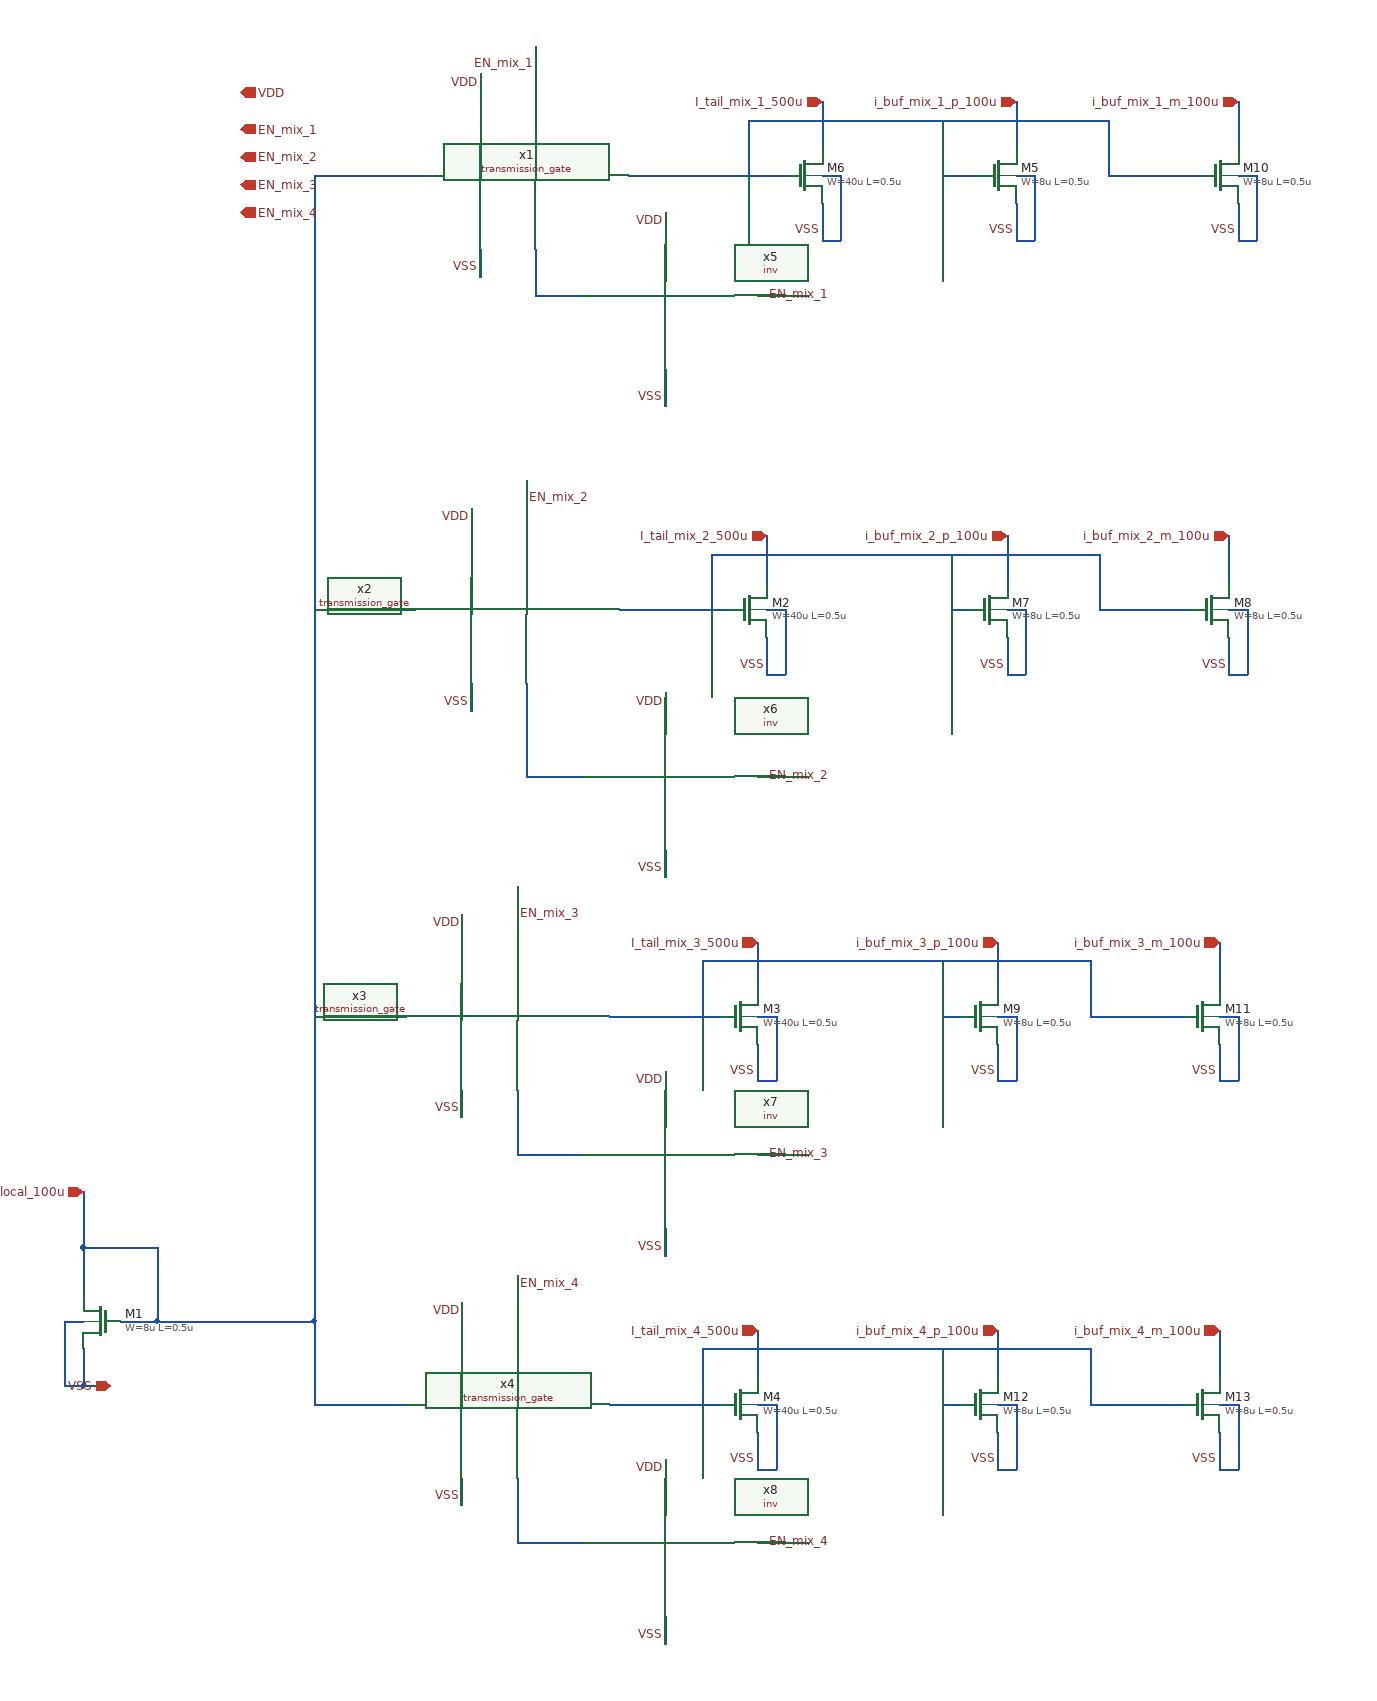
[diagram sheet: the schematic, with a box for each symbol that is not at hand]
v {xschem version=3.4.8RC file_version=1.3}
G {}
K {}
V {}
S {}
F {}
E {}
P 4 1 400 -950 {}
N 360 -770 360 -730 {lab=VSS}
N 360 -880 360 -830 {lab=I_local_100u}
N 360 -910 360 -880 {lab=I_local_100u}
N 360 -880 440 -880 {lab=I_local_100u}
N 440 -880 440 -800 {lab=I_local_100u}
N 400 -800 440 -800 {lab=I_local_100u}
N 340 -800 360 -800 {lab=VSS}
N 340 -800 340 -750 {lab=VSS}
N 340 -750 340 -730 {lab=VSS}
N 340 -730 360 -730 {lab=VSS}
N 440 -800 510 -800 {lab=I_local_100u}
N 360 -940 360 -910 {lab=I_local_100u}
N 1160 -2010 1160 -1970 {lab=VSS}
N 1160 -2120 1160 -2070 {lab=I_tail_mix_1_500u}
N 1160 -2040 1180 -2040 {lab=VSS}
N 1180 -2040 1180 -1970 {lab=VSS}
N 950 -2040 1060 -2040 {lab=#net1}
N 790 -2150 790 -2120 {lab=VDD}
N 610 -1910 610 -1630 {lab=I_local_100u}
N 610 -2040 730 -2040 {lab=I_local_100u}
N 610 -820 610 -800 {lab=I_local_100u}
N 610 -1630 610 -1390 {lab=I_local_100u}
N 790 -1960 790 -1930 {lab=VSS}
N 850 -2180 850 -2120 {lab=EN_mix_1}
N 850 -1960 850 -1920 {lab=#net2}
N 360 -730 390 -730 {lab=VSS}
N 1160 -1970 1180 -1970 {lab=VSS}
N 510 -800 610 -800 {lab=I_local_100u}
N 1100 -1540 1100 -1500 {lab=VSS}
N 1100 -1650 1100 -1600 {lab=I_tail_mix_2_500u}
N 1100 -1570 1120 -1570 {lab=VSS}
N 1120 -1570 1120 -1500 {lab=VSS}
N 1100 -1500 1120 -1500 {lab=VSS}
N 1000 -1570 1060 -1570 {lab=#net3}
N 1090 -1100 1090 -1060 {lab=VSS}
N 1090 -1210 1090 -1160 {lab=I_tail_mix_3_500u}
N 1090 -1130 1110 -1130 {lab=VSS}
N 1110 -1130 1110 -1060 {lab=VSS}
N 1090 -1060 1110 -1060 {lab=VSS}
N 990 -1130 1050 -1130 {lab=#net4}
N 1090 -680 1090 -640 {lab=VSS}
N 1090 -790 1090 -740 {lab=I_tail_mix_4_500u}
N 1090 -710 1110 -710 {lab=VSS}
N 1110 -710 1110 -640 {lab=VSS}
N 1090 -640 1110 -640 {lab=VSS}
N 990 -710 1050 -710 {lab=#net5}
N 780 -1680 780 -1650 {lab=VDD}
N 780 -1490 780 -1460 {lab=VSS}
N 840 -1710 840 -1650 {lab=EN_mix_2}
N 840 -1490 840 -1450 {lab=#net6}
N 770 -1240 770 -1210 {lab=VDD}
N 770 -1050 770 -1020 {lab=VSS}
N 830 -1270 830 -1210 {lab=EN_mix_3}
N 830 -1050 830 -1010 {lab=#net7}
N 770 -820 770 -790 {lab=VDD}
N 770 -630 770 -600 {lab=VSS}
N 830 -850 830 -790 {lab=EN_mix_4}
N 830 -630 830 -590 {lab=#net8}
N 930 -710 990 -710 {lab=#net5}
N 620 -710 710 -710 {lab=I_local_100u}
N 610 -1130 710 -1130 {lab=I_local_100u}
N 610 -710 620 -710 {lab=I_local_100u}
N 610 -1570 720 -1570 {lab=I_local_100u}
N 610 -2040 610 -1910 {lab=I_local_100u}
N 850 -1910 900 -1910 {lab=#net2}
N 850 -1920 850 -1910 {lab=#net2}
N 1090 -1910 1120 -1910 {lab=EN_mix_1}
N 1060 -2040 1120 -2040 {lab=#net1}
N 990 -2000 990 -1980 {lab=VDD}
N 990 -1830 990 -1790 {lab=VSS}
N 610 -1390 610 -830 {lab=I_local_100u}
N 610 -830 610 -820 {lab=I_local_100u}
N 940 -1570 1000 -1570 {lab=#net3}
N 840 -1390 900 -1390 {lab=#net6}
N 840 -1450 840 -1390 {lab=#net6}
N 990 -1310 990 -1280 {lab=VSS}
N 990 -1480 990 -1460 {lab=VDD}
N 1090 -1390 1120 -1390 {lab=EN_mix_2}
N 930 -1130 990 -1130 {lab=#net4}
N 840 -980 900 -980 {lab=#net7}
N 990 -900 990 -870 {lab=VSS}
N 990 -1070 990 -1050 {lab=VDD}
N 1090 -980 1120 -980 {lab=EN_mix_3}
N 830 -980 840 -980 {lab=#net7}
N 830 -1010 830 -980 {lab=#net7}
N 610 -800 610 -710 {lab=I_local_100u}
N 840 -560 900 -560 {lab=#net8}
N 990 -480 990 -450 {lab=VSS}
N 990 -650 990 -630 {lab=VDD}
N 1090 -560 1120 -560 {lab=EN_mix_4}
N 830 -560 840 -560 {lab=#net8}
N 830 -590 830 -560 {lab=#net8}
N 1370 -2010 1370 -1970 {lab=VSS}
N 1370 -2120 1370 -2070 {lab=i_buf_mix_1_p_100u}
N 1370 -2040 1390 -2040 {lab=VSS}
N 1390 -2040 1390 -1970 {lab=VSS}
N 1370 -1970 1390 -1970 {lab=VSS}
N 1610 -2010 1610 -1970 {lab=VSS}
N 1610 -2120 1610 -2070 {lab=i_buf_mix_1_m_100u}
N 1610 -2040 1630 -2040 {lab=VSS}
N 1630 -2040 1630 -1970 {lab=VSS}
N 1610 -1970 1630 -1970 {lab=VSS}
N 1470 -2100 1470 -2040 {lab=#net1}
N 1470 -2040 1480 -2040 {lab=#net1}
N 1480 -2040 1570 -2040 {lab=#net1}
N 1360 -1540 1360 -1500 {lab=VSS}
N 1360 -1650 1360 -1600 {lab=i_buf_mix_2_p_100u}
N 1360 -1570 1380 -1570 {lab=VSS}
N 1380 -1570 1380 -1500 {lab=VSS}
N 1360 -1500 1380 -1500 {lab=VSS}
N 1600 -1540 1600 -1500 {lab=VSS}
N 1600 -1650 1600 -1600 {lab=i_buf_mix_2_m_100u}
N 1600 -1570 1620 -1570 {lab=VSS}
N 1620 -1570 1620 -1500 {lab=VSS}
N 1600 -1500 1620 -1500 {lab=VSS}
N 1460 -1630 1460 -1570 {lab=#net3}
N 1460 -1570 1470 -1570 {lab=#net3}
N 1470 -1570 1560 -1570 {lab=#net3}
N 1350 -1100 1350 -1060 {lab=VSS}
N 1350 -1210 1350 -1160 {lab=i_buf_mix_3_p_100u}
N 1350 -1130 1370 -1130 {lab=VSS}
N 1370 -1130 1370 -1060 {lab=VSS}
N 1350 -1060 1370 -1060 {lab=VSS}
N 1590 -1100 1590 -1060 {lab=VSS}
N 1590 -1210 1590 -1160 {lab=i_buf_mix_3_m_100u}
N 1590 -1130 1610 -1130 {lab=VSS}
N 1610 -1130 1610 -1060 {lab=VSS}
N 1590 -1060 1610 -1060 {lab=VSS}
N 1450 -1190 1450 -1130 {lab=#net4}
N 1450 -1130 1460 -1130 {lab=#net4}
N 1460 -1130 1550 -1130 {lab=#net4}
N 1350 -680 1350 -640 {lab=VSS}
N 1350 -790 1350 -740 {lab=i_buf_mix_4_p_100u}
N 1350 -710 1370 -710 {lab=VSS}
N 1370 -710 1370 -640 {lab=VSS}
N 1350 -640 1370 -640 {lab=VSS}
N 1590 -680 1590 -640 {lab=VSS}
N 1590 -790 1590 -740 {lab=i_buf_mix_4_m_100u}
N 1590 -710 1610 -710 {lab=VSS}
N 1610 -710 1610 -640 {lab=VSS}
N 1590 -640 1610 -640 {lab=VSS}
N 1450 -770 1450 -710 {lab=#net5}
N 1450 -710 1460 -710 {lab=#net5}
N 1460 -710 1550 -710 {lab=#net5}
N 1080 -2100 1080 -2040 {lab=#net1}
N 1080 -2100 1470 -2100 {lab=#net1}
N 1290 -2040 1330 -2040 {lab=#net1}
N 1040 -1630 1460 -1630 {lab=#net3}
N 1040 -1630 1040 -1570 {lab=#net3}
N 1300 -1570 1320 -1570 {lab=#net3}
N 1300 -1630 1300 -1570 {lab=#net3}
N 1030 -1190 1450 -1190 {lab=#net4}
N 1030 -1190 1030 -1130 {lab=#net4}
N 1290 -1130 1310 -1130 {lab=#net4}
N 1290 -1190 1290 -1130 {lab=#net4}
N 1030 -770 1450 -770 {lab=#net5}
N 1030 -770 1030 -710 {lab=#net5}
N 1290 -710 1310 -710 {lab=#net5}
N 1290 -770 1290 -710 {lab=#net5}
N 1290 -2100 1290 -2040 {lab=#net1}
C {symbols/nfet_03v3.sym} 380 -800 0 1 {name=M1
L=0.5u
W=8u
nf=2
m=1
ad="'int((nf+1)/2) * W/nf * 0.18u'"
pd="'2*int((nf+1)/2) * (W/nf + 0.18u)'"
as="'int((nf+2)/2) * W/nf * 0.18u'"
ps="'2*int((nf+2)/2) * (W/nf + 0.18u)'"
nrd="'0.18u / W'" nrs="'0.18u / W'"
sa=0 sb=0 sd=0
model=nfet_03v3
spiceprefix=X
}
C {iopin.sym} 360 -940 0 0 {name=p5 lab=I_local_100u}
C {title.sym} 190 -60 0 0 {name=l1 author="Stefan Schippers"}
C {symbols/nfet_03v3.sym} 1140 -2040 0 0 {name=M6
L=0.5u
W=40u
nf=10
m=1
ad="'int((nf+1)/2) * W/nf * 0.18u'"
pd="'2*int((nf+1)/2) * (W/nf + 0.18u)'"
as="'int((nf+2)/2) * W/nf * 0.18u'"
ps="'2*int((nf+2)/2) * (W/nf + 0.18u)'"
nrd="'0.18u / W'" nrs="'0.18u / W'"
sa=0 sb=0 sd=0
model=nfet_03v3
spiceprefix=X
}
C {iopin.sym} 1160 -2120 0 0 {name=p12 lab=I_tail_mix_1_500u}
C {iopin.sym} 530 -2130 0 1 {name=p13 lab=VDD}
C {iopin.sym} 390 -730 0 0 {name=p2 lab=VSS}
C {lab_wire.sym} 790 -1940 0 0 {name=p14 sig_type=std_logic lab=VSS}
C {lab_wire.sym} 1160 -1980 0 0 {name=p15 sig_type=std_logic lab=VSS}
C {iopin.sym} 530 -2090 0 1 {name=p16 lab=EN_mix_1}
C {designs/digital/schematic/transmission_gate.sym} 850 -2040 0 0 {name=x1}
C {symbols/nfet_03v3.sym} 1080 -1570 0 0 {name=M2
L=0.5u
W=40u
nf=10
m=1
ad="'int((nf+1)/2) * W/nf * 0.18u'"
pd="'2*int((nf+1)/2) * (W/nf + 0.18u)'"
as="'int((nf+2)/2) * W/nf * 0.18u'"
ps="'2*int((nf+2)/2) * (W/nf + 0.18u)'"
nrd="'0.18u / W'" nrs="'0.18u / W'"
sa=0 sb=0 sd=0
model=nfet_03v3
spiceprefix=X
}
C {iopin.sym} 1100 -1650 0 0 {name=p1 lab=I_tail_mix_2_500u}
C {lab_wire.sym} 1100 -1510 0 0 {name=p3 sig_type=std_logic lab=VSS}
C {symbols/nfet_03v3.sym} 1070 -1130 0 0 {name=M3
L=0.5u
W=40u
nf=10
m=1
ad="'int((nf+1)/2) * W/nf * 0.18u'"
pd="'2*int((nf+1)/2) * (W/nf + 0.18u)'"
as="'int((nf+2)/2) * W/nf * 0.18u'"
ps="'2*int((nf+2)/2) * (W/nf + 0.18u)'"
nrd="'0.18u / W'" nrs="'0.18u / W'"
sa=0 sb=0 sd=0
model=nfet_03v3
spiceprefix=X
}
C {iopin.sym} 1090 -1210 0 0 {name=p4 lab=I_tail_mix_3_500u}
C {lab_wire.sym} 1090 -1070 0 0 {name=p6 sig_type=std_logic lab=VSS}
C {symbols/nfet_03v3.sym} 1070 -710 0 0 {name=M4
L=0.5u
W=40u
nf=10
m=1
ad="'int((nf+1)/2) * W/nf * 0.18u'"
pd="'2*int((nf+1)/2) * (W/nf + 0.18u)'"
as="'int((nf+2)/2) * W/nf * 0.18u'"
ps="'2*int((nf+2)/2) * (W/nf + 0.18u)'"
nrd="'0.18u / W'" nrs="'0.18u / W'"
sa=0 sb=0 sd=0
model=nfet_03v3
spiceprefix=X
}
C {iopin.sym} 1090 -790 0 0 {name=p7 lab=I_tail_mix_4_500u}
C {lab_wire.sym} 1090 -650 0 0 {name=p8 sig_type=std_logic lab=VSS}
C {lab_wire.sym} 780 -1470 0 0 {name=p10 sig_type=std_logic lab=VSS}
C {designs/digital/schematic/transmission_gate.sym} 840 -1570 0 0 {name=x2}
C {lab_wire.sym} 770 -1030 0 0 {name=p20 sig_type=std_logic lab=VSS}
C {designs/digital/schematic/transmission_gate.sym} 830 -1130 0 0 {name=x3}
C {lab_wire.sym} 770 -610 0 0 {name=p24 sig_type=std_logic lab=VSS}
C {designs/digital/schematic/transmission_gate.sym} 830 -710 0 0 {name=x4}
C {digital/schematic/inv.sym} 990 -1920 0 1 {name=x5}
C {lab_wire.sym} 990 -1800 0 0 {name=p17 sig_type=std_logic lab=VSS}
C {iopin.sym} 530 -2060 0 1 {name=p9 lab=EN_mix_2}
C {iopin.sym} 530 -2030 0 1 {name=p11 lab=EN_mix_3}
C {iopin.sym} 530 -2000 0 1 {name=p18 lab=EN_mix_4}
C {lab_wire.sym} 790 -2140 0 0 {name=p19 sig_type=std_logic lab=VDD}
C {lab_wire.sym} 780 -1670 0 0 {name=p21 sig_type=std_logic lab=VDD}
C {lab_wire.sym} 770 -1230 0 0 {name=p22 sig_type=std_logic lab=VDD}
C {lab_wire.sym} 770 -810 0 0 {name=p23 sig_type=std_logic lab=VDD}
C {lab_wire.sym} 850 -2160 0 0 {name=p25 sig_type=std_logic lab=EN_mix_1}
C {lab_wire.sym} 990 -1990 0 0 {name=p26 sig_type=std_logic lab=VDD}
C {lab_wire.sym} 1100 -1910 0 1 {name=p27 sig_type=std_logic lab=EN_mix_1}
C {digital/schematic/inv.sym} 990 -1400 0 1 {name=x6}
C {lab_wire.sym} 840 -1690 0 1 {name=p28 sig_type=std_logic lab=EN_mix_2}
C {lab_wire.sym} 1100 -1390 0 1 {name=p29 sig_type=std_logic lab=EN_mix_2}
C {lab_wire.sym} 990 -1470 0 0 {name=p30 sig_type=std_logic lab=VDD}
C {lab_wire.sym} 990 -1290 0 0 {name=p31 sig_type=std_logic lab=VSS}
C {digital/schematic/inv.sym} 990 -990 0 1 {name=x7}
C {lab_wire.sym} 1100 -980 0 1 {name=p32 sig_type=std_logic lab=EN_mix_3}
C {lab_wire.sym} 990 -1060 0 0 {name=p33 sig_type=std_logic lab=VDD}
C {lab_wire.sym} 990 -880 0 0 {name=p34 sig_type=std_logic lab=VSS}
C {lab_wire.sym} 830 -1240 0 1 {name=p35 sig_type=std_logic lab=EN_mix_3}
C {digital/schematic/inv.sym} 990 -570 0 1 {name=x8}
C {lab_wire.sym} 1100 -560 0 1 {name=p36 sig_type=std_logic lab=EN_mix_4}
C {lab_wire.sym} 990 -640 0 0 {name=p37 sig_type=std_logic lab=VDD}
C {lab_wire.sym} 990 -460 0 0 {name=p38 sig_type=std_logic lab=VSS}
C {lab_wire.sym} 830 -840 0 1 {name=p39 sig_type=std_logic lab=EN_mix_4}
C {symbols/nfet_03v3.sym} 1350 -2040 0 0 {name=M5
L=0.5u
W=8u
nf=10
m=1
ad="'int((nf+1)/2) * W/nf * 0.18u'"
pd="'2*int((nf+1)/2) * (W/nf + 0.18u)'"
as="'int((nf+2)/2) * W/nf * 0.18u'"
ps="'2*int((nf+2)/2) * (W/nf + 0.18u)'"
nrd="'0.18u / W'" nrs="'0.18u / W'"
sa=0 sb=0 sd=0
model=nfet_03v3
spiceprefix=X
}
C {lab_wire.sym} 1370 -1980 0 0 {name=p42 sig_type=std_logic lab=VSS}
C {symbols/nfet_03v3.sym} 1590 -2040 0 0 {name=M10
L=0.5u
W=8u
nf=10
m=1
ad="'int((nf+1)/2) * W/nf * 0.18u'"
pd="'2*int((nf+1)/2) * (W/nf + 0.18u)'"
as="'int((nf+2)/2) * W/nf * 0.18u'"
ps="'2*int((nf+2)/2) * (W/nf + 0.18u)'"
nrd="'0.18u / W'" nrs="'0.18u / W'"
sa=0 sb=0 sd=0
model=nfet_03v3
spiceprefix=X
}
C {lab_wire.sym} 1610 -1980 0 0 {name=p73 sig_type=std_logic lab=VSS}
C {iopin.sym} 1370 -2120 0 0 {name=p40 lab=i_buf_mix_1_p_100u}
C {iopin.sym} 1610 -2120 0 0 {name=p72 lab=i_buf_mix_1_m_100u}
C {symbols/nfet_03v3.sym} 1340 -1570 0 0 {name=M7
L=0.5u
W=8u
nf=10
m=1
ad="'int((nf+1)/2) * W/nf * 0.18u'"
pd="'2*int((nf+1)/2) * (W/nf + 0.18u)'"
as="'int((nf+2)/2) * W/nf * 0.18u'"
ps="'2*int((nf+2)/2) * (W/nf + 0.18u)'"
nrd="'0.18u / W'" nrs="'0.18u / W'"
sa=0 sb=0 sd=0
model=nfet_03v3
spiceprefix=X
}
C {lab_wire.sym} 1360 -1510 0 0 {name=p43 sig_type=std_logic lab=VSS}
C {symbols/nfet_03v3.sym} 1580 -1570 0 0 {name=M8
L=0.5u
W=8u
nf=10
m=1
ad="'int((nf+1)/2) * W/nf * 0.18u'"
pd="'2*int((nf+1)/2) * (W/nf + 0.18u)'"
as="'int((nf+2)/2) * W/nf * 0.18u'"
ps="'2*int((nf+2)/2) * (W/nf + 0.18u)'"
nrd="'0.18u / W'" nrs="'0.18u / W'"
sa=0 sb=0 sd=0
model=nfet_03v3
spiceprefix=X
}
C {lab_wire.sym} 1600 -1510 0 0 {name=p44 sig_type=std_logic lab=VSS}
C {iopin.sym} 1360 -1650 0 0 {name=p45 lab=i_buf_mix_2_p_100u}
C {iopin.sym} 1600 -1650 0 0 {name=p46 lab=i_buf_mix_2_m_100u}
C {symbols/nfet_03v3.sym} 1330 -1130 0 0 {name=M9
L=0.5u
W=8u
nf=10
m=1
ad="'int((nf+1)/2) * W/nf * 0.18u'"
pd="'2*int((nf+1)/2) * (W/nf + 0.18u)'"
as="'int((nf+2)/2) * W/nf * 0.18u'"
ps="'2*int((nf+2)/2) * (W/nf + 0.18u)'"
nrd="'0.18u / W'" nrs="'0.18u / W'"
sa=0 sb=0 sd=0
model=nfet_03v3
spiceprefix=X
}
C {lab_wire.sym} 1350 -1070 0 0 {name=p47 sig_type=std_logic lab=VSS}
C {symbols/nfet_03v3.sym} 1570 -1130 0 0 {name=M11
L=0.5u
W=8u
nf=10
m=1
ad="'int((nf+1)/2) * W/nf * 0.18u'"
pd="'2*int((nf+1)/2) * (W/nf + 0.18u)'"
as="'int((nf+2)/2) * W/nf * 0.18u'"
ps="'2*int((nf+2)/2) * (W/nf + 0.18u)'"
nrd="'0.18u / W'" nrs="'0.18u / W'"
sa=0 sb=0 sd=0
model=nfet_03v3
spiceprefix=X
}
C {lab_wire.sym} 1590 -1070 0 0 {name=p48 sig_type=std_logic lab=VSS}
C {iopin.sym} 1350 -1210 0 0 {name=p74 lab=i_buf_mix_3_p_100u}
C {iopin.sym} 1590 -1210 0 0 {name=p75 lab=i_buf_mix_3_m_100u}
C {symbols/nfet_03v3.sym} 1330 -710 0 0 {name=M12
L=0.5u
W=8u
nf=10
m=1
ad="'int((nf+1)/2) * W/nf * 0.18u'"
pd="'2*int((nf+1)/2) * (W/nf + 0.18u)'"
as="'int((nf+2)/2) * W/nf * 0.18u'"
ps="'2*int((nf+2)/2) * (W/nf + 0.18u)'"
nrd="'0.18u / W'" nrs="'0.18u / W'"
sa=0 sb=0 sd=0
model=nfet_03v3
spiceprefix=X
}
C {lab_wire.sym} 1350 -650 0 0 {name=p76 sig_type=std_logic lab=VSS}
C {symbols/nfet_03v3.sym} 1570 -710 0 0 {name=M13
L=0.5u
W=8u
nf=10
m=1
ad="'int((nf+1)/2) * W/nf * 0.18u'"
pd="'2*int((nf+1)/2) * (W/nf + 0.18u)'"
as="'int((nf+2)/2) * W/nf * 0.18u'"
ps="'2*int((nf+2)/2) * (W/nf + 0.18u)'"
nrd="'0.18u / W'" nrs="'0.18u / W'"
sa=0 sb=0 sd=0
model=nfet_03v3
spiceprefix=X
}
C {lab_wire.sym} 1590 -650 0 0 {name=p77 sig_type=std_logic lab=VSS}
C {iopin.sym} 1350 -790 0 0 {name=p78 lab=i_buf_mix_4_p_100u}
C {iopin.sym} 1590 -790 0 0 {name=p79 lab=i_buf_mix_4_m_100u}
